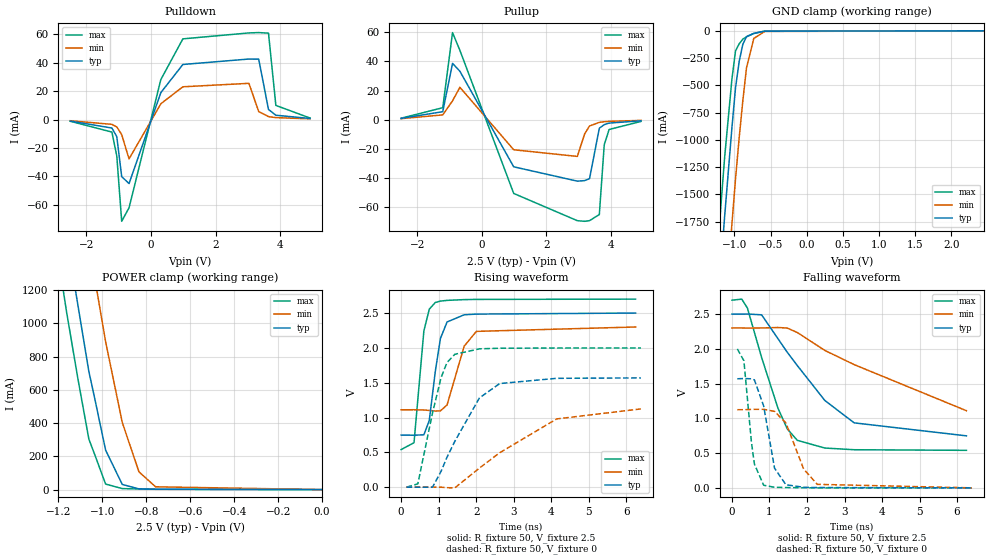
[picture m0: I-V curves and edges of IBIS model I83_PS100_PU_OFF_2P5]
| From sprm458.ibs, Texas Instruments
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|   Model Cell I83_PS100_PU_OFF_2P5
|IDG09_OUI83I83_PS100_PU_OFF_2P5
[Model]   I83_PS100_PU_OFF_2P5
Model_type   I/O
Polarity   Non-Inverting
Enable   Active-Low
Vinl =  0.7V
Vinh =  1.7V
Cref =  15pF
Rref =  100.00M
Vref =  0V
Vmeas =  1.25
C_comp   4.785p   4.743p   5.018p
[Model Spec]
Vinl   0.7V   0.7V   0.7V
Vinh   1.7V   1.7V   1.7V
[Temperature Range]   25   125   -40
[Voltage Range]   2.5   2.3   2.7
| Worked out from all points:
|   slope of the pulldown table from 0 to 0.375 V, typ, clamps not added: 16.7 ohm
|   slope of the pullup table from 0 to 0.375 V, typ, clamps not added: 24.3 ohm
|   GND clamp passes 1 mA (typ) near -0.53 V on its own axis
|   POWER clamp passes 1 mA (typ) near -0.68 V on its own axis
|   rising waveform, R_fixture 50, V_fixture 2.5: 20-80 % time 263ps typ, 361ps min, 200ps max; typ from 0.748 V to 2.5 V
|   rising waveform, R_fixture 50, V_fixture 0: 20-80 % time 922ps typ, 1.79ns min, 494ps max; typ from 0 V to 1.57 V
|   falling waveform, R_fixture 50, V_fixture 2.5: 20-80 % time 1.56ns typ, 2.86ns min, 773ps max; typ from 2.5 V to 0.748 V
|   falling waveform, R_fixture 50, V_fixture 0: 20-80 % time 299ps typ, 486ps min, 212ps max; typ from 1.57 V to 0 V
| Nom Voltages:
|   VDD=1.1, VDDS=2.5, VSS=0, VSSS=0
| Min Voltages:
|   VDD=1, VDDS=2.3, VSS=0, VSSS=0
| Max Voltages:
|   VDD=1.2, VDDS=2.7, VSS=0, VSSS=0
[POWER_clamp]
|   voltage   I(typ)   I(min)   I(max)
-2.5V     14.33A     15.07A     13.92A
-1.187V   1.745A     2.55A      1.279A
-1.162V   1.527A     2.329A     1.065A
-1.111V   1.11A      1.897A     667.8mA
-1.061V   710.2mA    1.474A     303.2mA
-1.035V   552.6mA    1.279A     213.2mA
-1.01V    395mA      1.084A     123.2mA
-984.8mV  237.4mA    889.6mA    33.23mA
-909.1mV  31.08mA    404.1mA    6.07mA
-833.3mV  4.345mA    107.2mA    3.75mA
-757.6mV  1.884mA    16.85mA    2.357mA
0V        70.97pA    11.86nA    701.7fA
[Pulldown]
|   voltage   I(typ)   I(min)   I(max)
-2.5V     -1.029mA   -780.5uA   -1.158mA
-1.212V   -5.915mA   -3.318mA   -8.754mA
-1.061V   -11.95mA   -5.187mA   -25.54mA
-909.1mV  -40.08mA   -10.52mA   -71.53mA
-681.8mV  -44.99mA   -27.63mA   -62.02mA
303mV     19mA       11.15mA    28.2mA
984.8mV   38.8mA     23.1mA     56.82mA
3.03V     42.63mA    25.53mA    61mA
3.333V    42.55mA    5.654mA    61.25mA
3.636V    7.154mA    2.123mA    60.83mA
3.864V    3.092mA    1.414mA    10.01mA
4.924V    800.1uA    540.5uA    1.094mA
[Pullup]
|   voltage   I(typ)   I(min)   I(max)
-2.5V     856.4uA    691.1uA    993.5uA
-1.212V   5.469mA    3.267mA    8.205mA
-909.1mV  38.64mA    12.9mA     59.79mA
-681.8mV  33.25mA    22.23mA    47.64mA
984.8mV   -32.38mA   -20.68mA   -50.65mA
2.955V    -42.21mA   -25.24mA   -69.37mA
3.182V    -41.85mA   -9.733mA   -69.79mA
3.333V    -40.48mA   -4.356mA   -69.34mA
3.636V    -5.897mA   -1.881mA   -65.15mA
3.788V    -3.419mA   -1.448mA   -17.23mA
3.939V    -2.377mA   -1.175mA   -6.755mA
4.924V    -777.2uA   -520.7uA   -1.228mA
[GND_clamp]
|   voltage   I(typ)   I(min)   I(max)
-2.5V     -14.77A    -15.66A    -14.27A
-1.237V   -2.604A    -3.547A    -2.05A
-1.187V   -2.151A    -3.09A     -1.601A
-1.136V   -1.705A    -2.638A    -1.162A
-1.035V   -889mA     -1.772A    -443mA
-984.8mV  -521mA     -1.356A    -183.2mA
-934.3mV  -279.7mA   -978.6mA   -118.6mA
-883.8mV  -123.6mA   -639.8mA   -76mA
-833.3mV  -52.7mA    -339.6mA   -55.37mA
-732.3mV  -22.85mA   -70.05mA   -24.85mA
-580.8mV  -3.273mA   -5.948mA   -2.187mA
2.449V    68.03pA    128.2nA    652.8fA
[Ramp]
| variable   typ   min   max
dV/dt_f  1.0589568/1.5611978n 0.71930505/2.8610186n  1.3063898/0.7774558n
dV/dt_r 0.94926811/0.92627565n 0.68141088/1.7999976n  1.2075606/0.4968465n
R_load = 50
[Rising Waveform]
R_fixture = 50
V_fixture = 2.5
V_fixture_min = 2.3
V_fixture_max = 2.7
|   time   V(typ)   V(min)   V(max)
0s        748.2mV    1.11V      539.9mV
343.1ps   746mV      1.112V     638.6mV
606ps     752.5mV    1.108V     2.243V
750.2ps   958.3mV    1.102V     2.556V
911.2ps   1.664V     1.093V     2.652V
1.047ns   2.135V     1.096V     2.672V
1.224ns   2.372V     1.18V      2.682V
1.68ns    2.475V     2.024V     2.693V
2.006ns   2.485V     2.237V     2.696V
6.25ns    2.5V       2.3V       2.7V
[Rising Waveform]
R_fixture = 50
V_fixture = 0
V_fixture_min = 0
V_fixture_max = 0
|   time   V(typ)   V(min)   V(max)
143.1ps   0V         0V         0V
444.4ps   0V         0V         48.28mV
835.9ps   0V         0V         1.065V
1.063ns   225.8mV    0V         1.571V
1.222ns   429.5mV    -7.347mV   1.789V
1.431ns   658.6mV    -9.691mV   1.908V
2.086ns   1.281V     274mV      1.986V
2.628ns   1.488V     494.6mV    1.995V
4.147ns   1.563V     980mV      1.998V
6.393ns   1.569V     1.124V     1.999V
[Falling Waveform]
R_fixture = 50
V_fixture = 2.5
V_fixture_min = 2.3
V_fixture_max = 2.7
|   time   V(typ)   V(min)   V(max)
0s        2.5V       2.3V       2.7V
259.9ps   2.499V     2.3V       2.715V
411.1ps   2.501V     2.299V     2.587V
790.5ps   2.489V     2.3V       1.875V
1.226ns   2.146V     2.307V     1.146V
1.473ns   1.951V     2.299V     849.3mV
1.741ns   1.76V      2.235V     683.8mV
2.476ns   1.257V     1.977V     572.8mV
3.257ns   935.1mV    1.773V     548.5mV
6.25ns    748.2mV    1.11V      539.9mV
[Falling Waveform]
R_fixture = 50
V_fixture = 0
V_fixture_min = 0
V_fixture_max = 0
|   time   V(typ)   V(min)   V(max)
143.1ps   1.569V     1.124V     1.999V
318.1ps   1.573V     1.124V     1.828V
518.2ps   1.569V     1.128V     658.3mV
598.5ps   1.553V     1.13V      340.8mV
844.9ps   1.177V     1.13V      37.71mV
1.135ns   282.8mV    1.1V       8.505mV
1.439ns   44.78mV    932.7mV    4.572mV
1.909ns   8.299mV    273.1mV    2.195mV
2.273ns   4.538mV    50.58mV    0V
6.393ns   0V         0V         0V
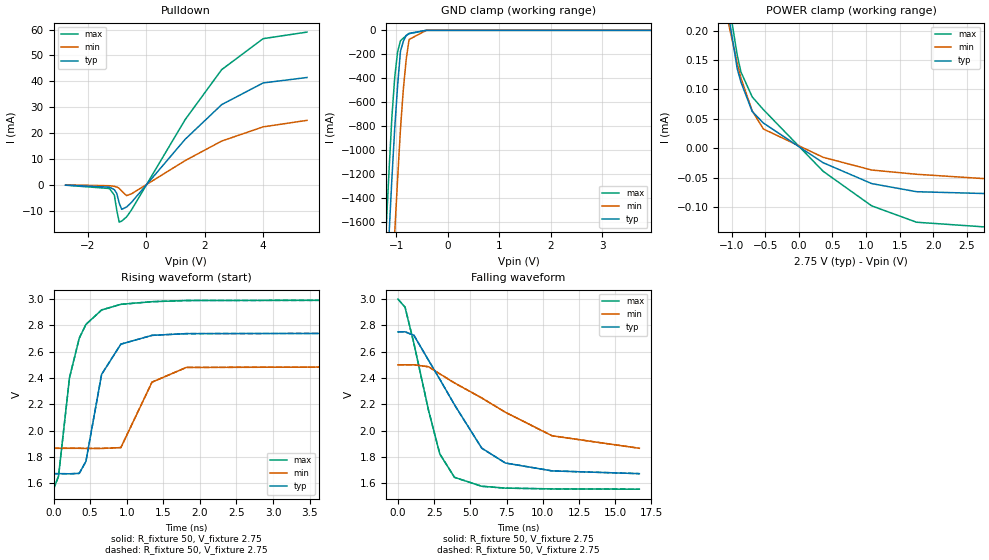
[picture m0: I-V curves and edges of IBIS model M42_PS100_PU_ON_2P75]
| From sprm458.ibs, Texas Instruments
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|   Model Cell M42_PS100_PU_ON_2P75
|IDG09_OUM42_PS100_PU_ON_2P75
[Model]   M42_PS100_PU_ON_2P75
Model_type   I/O_open_drain
Polarity   Non-Inverting
Enable   Active-Low
Vinl =  0.7V
Vinh =  1.7V
Cref =  15pF
Rref =  100.00M
Vref =  0V
Vmeas =  1.375
C_comp   4.287p   4.203p   4.656p
[Model Spec]
Vinl   0.7V   0.7V   0.7V
Vinh   1.7V   1.7V   1.7V
[Temperature Range]   25   125   -40
[Voltage Range]   2.75   2.5   3
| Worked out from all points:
|   slope of the pulldown table from 0 to 0.412 V, typ, clamps not added: 73.2 ohm
|   GND clamp passes 1 mA (typ) near -0.51 V on its own axis
|   POWER clamp passes 1 mA (typ) near -1.78 V on its own axis
|   rising waveform, R_fixture 50, V_fixture 2.75: 20-80 % time 256ps typ, 271ps min, 256ps max; typ from 1.67 V to 2.75 V
|   rising waveform, R_fixture 50, V_fixture 2.75: 20-80 % time 256ps typ, 271ps min, 256ps max; typ from 1.67 V to 2.75 V
|   falling waveform, R_fixture 50, V_fixture 2.75: 20-80 % time 3.52ns typ, 6.06ns min, 1.83ns max; typ from 2.75 V to 1.67 V
|   falling waveform, R_fixture 50, V_fixture 2.75: 20-80 % time 3.52ns typ, 6.06ns min, 1.83ns max; typ from 2.75 V to 1.67 V
| Nom Voltages:
|   VDD=1.1, VDDS=2.75, VSS=0, VSSS=0
| Min Voltages:
|   VDD=1, VDDS=2.5, VSS=0, VSSS=0
| Max Voltages:
|   VDD=1.2, VDDS=3, VSS=0, VSSS=0
[POWER_clamp]
|   voltage   I(typ)   I(min)   I(max)
-2.75V    2.08mA     1.234mA    3.107mA
-1.139V   317.1uA    263.9uA    365.7uA
-1.083V   262.8uA    232.7uA    289.5uA
-1.028V   213.9uA    202.4uA    237.9uA
-916.7mV  135.2uA    144.5uA    158.1uA
-861.1mV  112.4uA    119.2uA    129.5uA
-694.4mV  62.42uA    63.54uA    87.35uA
-527.8mV  42.79uA    32.64uA    65.59uA
361.1mV   -24.85uA   -15.58uA   -39.38uA
1.083V    -60.32uA   -37.24uA   -98.22uA
1.75V     -74.15uA   -44.46uA   -126.1uA
2.75V     -77.21uA   -51.82uA   -134uA
[Pulldown]
|   voltage   I(typ)   I(min)   I(max)
-2.75V    -158.8uA   -86.66uA   -198.2uA
-1.25V    -956.2uA   -405.1uA   -1.484mA
-1.083V   -1.926mA   -649.1uA   -4.057mA
-1V       -3.428mA   -904uA     -10mA
-916.7mV  -7.154mA   -1.402mA   -14.51mA
-833.3mV  -9.533mA   -2.46mA    -14.08mA
-666.7mV  -8.643mA   -4.227mA   -12.48mA
-500mV    -6.858mA   -3.549mA   -9.806mA
1.333V    17.54mA    9.305mA    25.13mA
2.583V    30.97mA    16.88mA    44.51mA
4V        39.37mA    22.37mA    56.5mA
5.5V      41.47mA    24.89mA    59.04mA
[GND_clamp]
|   voltage   I(typ)   I(min)   I(max)
-2.75V    -17.22A    -18.08A    -16.72A
-1.194V   -2.2A      -3.135A    -1.654A
-1.139V   -1.714A    -2.64A     -1.18A
-1.083V   -1.24A     -2.152A    -725.2mA
-1.028V   -818.3mA   -1.688A    -392.5mA
-972.2mV  -463.1mA   -1.245A    -180mA
-916.7mV  -175mA     -824.1mA   -87.58mA
-861.1mV  -92.28mA   -492.8mA   -65.08mA
-805.6mV  -42.38mA   -243.6mA   -45.26mA
-750mV    -25.29mA   -76.59mA   -28.12mA
-416.7mV  -124.6uA   -317.4uA   -143.5uA
5.5V      0A         0A         0A
[Ramp]
| variable   typ   min   max
dV/dt_f 0.64768466/3.5210456n 0.38170413/6.0699581n 0.86866181/1.8344096n
dV/dt_r 14.544267m/0.1149428n  10.95371m/0.1769077n 16.881275m/89.44357p
R_load = 50
[Rising Waveform]
R_fixture = 50
V_fixture = 2.75
V_fixture_min = 2.5
V_fixture_max = 3
|   time   V(typ)   V(min)   V(max)
0s        1.672V     1.865V     1.554V
68.5ps    1.672V     1.865V     1.653V
218.4ps   1.671V     1.865V     2.402V
351.4ps   1.674V     1.865V     2.702V
442.9ps   1.765V     1.864V     2.807V
657.1ps   2.427V     1.864V     2.917V
920.4ps   2.657V     1.87V      2.96V
1.346ns   2.724V     2.368V     2.98V
1.815ns   2.737V     2.48V      2.989V
16.67ns   2.75V      2.5V       3V
[Rising Waveform]
R_fixture = 50
V_fixture = 2.75
V_fixture_min = 2.5
V_fixture_max = 3
|   time   V(typ)   V(min)   V(max)
0s        1.672V     1.865V     1.554V
68.5ps    1.672V     1.865V     1.653V
218.4ps   1.671V     1.865V     2.402V
351.4ps   1.674V     1.865V     2.702V
442.9ps   1.765V     1.864V     2.807V
657.1ps   2.427V     1.864V     2.917V
920.4ps   2.657V     1.87V      2.96V
1.346ns   2.724V     2.368V     2.98V
1.815ns   2.737V     2.48V      2.989V
16.67ns   2.75V      2.5V       3V
[Falling Waveform]
R_fixture = 50
V_fixture = 2.75
V_fixture_min = 2.5
V_fixture_max = 3
|   time   V(typ)   V(min)   V(max)
0s        2.75V      2.5V       3V
493.1ps   2.751V     2.5V       2.938V
1.106ns   2.724V     2.5V       2.661V
2.115ns   2.534V     2.485V     2.153V
2.891ns   2.39V      2.431V     1.822V
3.905ns   2.196V     2.362V     1.644V
5.786ns   1.866V     2.248V     1.576V
7.416ns   1.753V     2.139V     1.562V
10.65ns   1.693V     1.96V      1.556V
16.67ns   1.672V     1.865V     1.554V
[Falling Waveform]
R_fixture = 50
V_fixture = 2.75
V_fixture_min = 2.5
V_fixture_max = 3
|   time   V(typ)   V(min)   V(max)
0s        2.75V      2.5V       3V
493.1ps   2.751V     2.5V       2.938V
1.106ns   2.724V     2.5V       2.661V
2.115ns   2.534V     2.485V     2.153V
2.891ns   2.39V      2.431V     1.822V
3.905ns   2.196V     2.362V     1.644V
5.786ns   1.866V     2.248V     1.576V
7.416ns   1.753V     2.139V     1.562V
10.65ns   1.693V     1.96V      1.556V
16.67ns   1.672V     1.865V     1.554V
